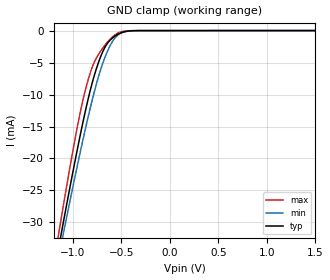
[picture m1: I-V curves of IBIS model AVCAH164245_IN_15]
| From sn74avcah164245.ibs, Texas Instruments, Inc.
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[Model]   AVCAH164245_IN_15
Model_type  Input
Vinl=0.49
Vinh=1.04
| variable   typ   min   max
C_comp   2.59pF   2.11pF   3.01pF
[Temperature Range]   40   100   -40
| Ambient temperature   25   85   -40
[Voltage range]   1.5   1.4   1.6
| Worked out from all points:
|   GND clamp passes 1 mA (typ) near -0.58 V on its own axis
[GND Clamp]
| AVCAH164245_IN_15
|   Voltage   I(typ)   I(min)   I(max)
-3.6V     -258.5mA   -242.3mA   -278mA
-1.165V   -35.44mA   -36.78mA   -33.39mA
-1.14V    -33.37mA   -34.87mA   -31.1mA
-1.115V   -31.31mA   -32.97mA   -28.83mA
-1.09V    -29.27mA   -31.08mA   -26.58mA
-950mV    -18.24mA   -20.81mA   -14.7mA
-840mV    -10.5mA    -13.3mA    -7.535mA
-780mV    -7.043mA   -9.603mA   -4.951mA
-705mV    -3.735mA   -5.691mA   -3.006mA
-585mV    -1.06mA    -1.53mA    -892.5uA
-380mV    -22.97uA   -30.19uA   -5.607uA
1.5V      138.7pA    855.7pA    21.09pA
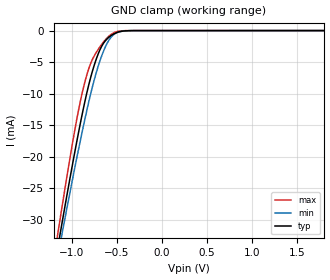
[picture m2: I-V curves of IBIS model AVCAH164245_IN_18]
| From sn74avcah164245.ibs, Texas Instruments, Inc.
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[Model]   AVCAH164245_IN_18
Model_type  Input
Vinl=0.5775
Vinh=1.2675
| variable   typ   min   max
C_comp   2.57pF   2.11pF   3.02pF
[Temperature Range]   40   100   -40
| Ambient temperature   25   85   -40
[Voltage range]   1.8   1.65   1.95
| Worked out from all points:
|   GND clamp passes 1 mA (typ) near -0.58 V on its own axis
[GND Clamp]
| AVCAH164245_IN_18
|   Voltage   I(typ)   I(min)   I(max)
-3.6V     -258.5mA   -242.3mA   -278mA
-1.15V    -34.2mA    -35.63mA   -32.02mA
-1.125V   -32.13mA   -33.73mA   -29.74mA
-1.1V     -30.08mA   -31.83mA   -27.48mA
-940mV    -17.49mA   -20.1mA    -13.94mA
-820mV    -9.271mA   -12.02mA   -6.55mA
-750mV    -5.585mA   -7.927mA   -4.068mA
-675mV    -2.758mA   -4.401mA   -2.383mA
-600mV    -1.25mA    -1.894mA   -1.094mA
-525mV    -489uA     -571uA     -316.1uA
-305mV    -2.806uA   -4.971uA   -342.3nA
1.8V      153pA      887.4pA    25.37pA
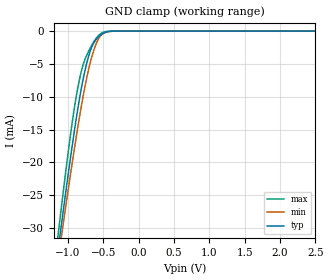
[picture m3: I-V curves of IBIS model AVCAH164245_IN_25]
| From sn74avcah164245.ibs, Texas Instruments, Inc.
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[Model]   AVCAH164245_IN_25
Model_type  Input
Vinl=0.7
Vinh=1.7
| variable   typ   min   max
C_comp   2.51pF   1.94pF   3.03pF
[Temperature Range]   40   100   -40
| Ambient temperature   25   85   -40
[Voltage range]   2.5   2.3   2.7
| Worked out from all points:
|   GND clamp passes 1 mA (typ) near -0.58 V on its own axis
[GND Clamp]
| AVCAH164245_IN_25
|   Voltage   I(typ)   I(min)   I(max)
-3.6V     -258.5mA   -242.3mA   -278mA
-1.135V   -32.95mA   -34.49mA   -30.65mA
-1.11V    -30.9mA    -32.59mA   -28.38mA
-1.085V   -28.86mA   -30.7mA    -26.14mA
-925mV    -16.38mA   -19.04mA   -12.82mA
-875mV    -12.81mA   -15.61mA   -9.498mA
-815mV    -8.975mA   -11.71mA   -6.321mA
-745mV    -5.359mA   -7.661mA   -3.939mA
-675mV    -2.758mA   -4.401mA   -2.383mA
-585mV    -1.06mA    -1.53mA    -892.5uA
-505mV    -356.6uA   -398.4uA   -204.9uA
2.5V      190pA      962.8pA    35.97pA
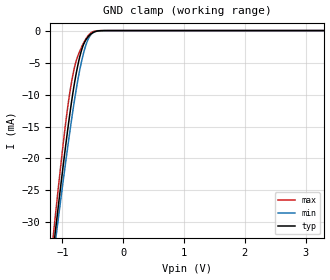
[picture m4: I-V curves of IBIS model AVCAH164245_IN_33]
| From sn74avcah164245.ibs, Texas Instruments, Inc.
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[Model]   AVCAH164245_IN_33
Model_type  Input
Vinl=0.8
Vinh=2
| variable   typ   min   max
C_comp   2.45pF   1.83pF   3.10pF
[Temperature Range]   40   100   -40
| Ambient temperature   25   85   -40
[Voltage range]   3.3   3   3.6
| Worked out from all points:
|   GND clamp passes 1 mA (typ) near -0.58 V on its own axis
[GND Clamp]
| AVCAH164245_IN_33
|   Voltage   I(typ)   I(min)   I(max)
-3.6V     -258.5mA   -242.3mA   -278mA
-1.16V    -35.03mA   -36.4mA    -32.93mA
-1.13V    -32.54mA   -34.11mA   -30.19mA
-1.105V   -30.49mA   -32.21mA   -27.93mA
-1.08V    -28.46mA   -30.33mA   -25.69mA
-935mV    -17.11mA   -19.74mA   -13.56mA
-815mV    -8.975mA   -11.71mA   -6.321mA
-750mV    -5.585mA   -7.927mA   -4.068mA
-675mV    -2.758mA   -4.401mA   -2.383mA
-590mV    -1.12mA    -1.646mA   -957.2uA
-500mV    -327.7uA   -363.5uA   -182.6uA
3.3V      240.1pA    1.053nA    49.57pA
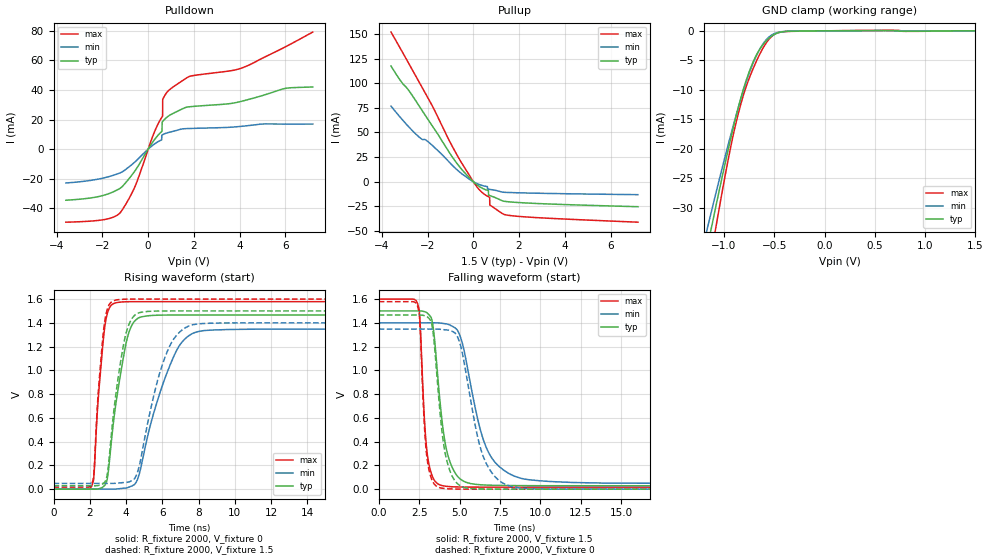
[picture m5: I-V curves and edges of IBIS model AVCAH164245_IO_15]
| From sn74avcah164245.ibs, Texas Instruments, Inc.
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[Model]   AVCAH164245_IO_15
Model_type  I/O
Vinl=0.49
Vinh=1.04
Enable   Active-Low
Vref =   0
Rref =   2000
Cref =   15p
Vmeas =   0.75
| variable   typ   min   max
C_comp   3.64pF   3.18pF   3.94pF
| C_pullup   2.35pF   0.32pF   4.30pF
| C_pulldown   3.11pF   0.98pF   4.70pF
| C_tri-state   3.64pF   3.18pF   3.94pF
[Temperature Range]   40   100   -40
| Ambient temperature   25   85   -40
[Voltage range]   1.5   1.4   1.6
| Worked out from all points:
|   slope of the pulldown table from 0 to 0.225 V, typ, clamps not added: 42 ohm
|   slope of the pullup table from 0 to 0.225 V, typ, clamps not added: 52.5 ohm
|   GND clamp passes 1 mA (typ) near -0.53 V on its own axis
|   rising waveform, R_fixture 2000, V_fixture 0: 20-80 % time 808ps typ, 1.58ns min, 449ps max; typ from 0 V to 1.47 V
|   falling waveform, R_fixture 2000, V_fixture 1.5: 20-80 % time 717ps typ, 1.42ns min, 370ps max; typ from 1.5 V to 0.029 V
|   rising waveform, R_fixture 2000, V_fixture 1.5: 20-80 % time 742ps typ, 1.31ns min, 428ps max; typ from 0.029 V to 1.5 V
|   falling waveform, R_fixture 2000, V_fixture 0: 20-80 % time 653ps typ, 1.22ns min, 348ps max; typ from 1.47 V to 0 V
[GND Clamp]
| AVCAH164245_IO_15
|   Voltage   I(typ)   I(min)   I(max)
-3.6V     -266.9mA   -231.6mA   -310.8mA
-1.17V    -37.13mA   -33.81mA   -42.25mA
-1.145V   -35.05mA   -32.04mA   -39.73mA
-1.12V    -32.98mA   -30.28mA   -37.22mA
-1.095V   -30.93mA   -28.54mA   -34.74mA
-1.07V    -28.91mA   -26.81mA   -32.29mA
-910mV    -16.61mA   -16.23mA   -17.83mA
-775mV    -8.202mA   -8.432mA   -9.247mA
-635mV    -2.878mA   -2.851mA   -3.659mA
-505mV    -672.1uA   -519.1uA   -682.9uA
-330mV    -58.96uA   -42.33uA   -86.88uA
1.5V      423.9pA    1.527uA    -44.14nA
[Pulldown]
| AVCAH164245_IO_15
|   Voltage   I(typ)   I(min)   I(max)
-3.6V     -34.57mA   -22.93mA   -49.45mA
-1.205V   -26.25mA   -15.91mA   -42.65mA
-545mV    -13.97mA   -8.197mA   -24.13mA
605mV     12.08mA    9.529mA    21.74mA
610mV     17.95mA    9.575mA    21.85mA
630mV     18.63mA    9.752mA    22.26mA
635mV     18.73mA    9.794mA    33.51mA
640mV     18.82mA    9.836mA    33.78mA
1.005V    23.49mA    11.71mA    41.12mA
1.815V    28.67mA    13.96mA    49.24mA
4.21V     32.88mA    15.63mA    55.57mA
7.2V      42.06mA    16.99mA    79.2mA
[Pullup]
| AVCAH164245_IO_15
|   Voltage   I(typ)   I(min)   I(max)
-3.6V     117.4mA    76.76mA    152mA
-2.53V    82.64mA    48.73mA    107.8mA
-1.915V   60.82mA    39.36mA    82.13mA
-685mV    17.59mA    11.5mA     25.93mA
160mV     -3.172mA   -1.894mA   -5.317mA
660mV     -9.044mA   -7.637mA   -15.18mA
665mV     -13.54mA   -7.655mA   -15.24mA
715mV     -14.07mA   -7.825mA   -15.71mA
720mV     -14.11mA   -7.841mA   -23.63mA
725mV     -14.15mA   -7.857mA   -23.74mA
1.66V     -20.65mA   -11.06mA   -34.53mA
7.2V      -25.41mA   -13.18mA   -41.13mA
[Ramp]
| AVCAH164245_IO_15
| variable   typ   min   max
dV/dt_r   0.88/8.11E-10   0.81/1.58E-09   0.95/4.52E-10
dV/dt_f   0.88/7.22E-10   0.81/1.42E-09   0.95/3.76E-10
R_load = 2000
[Rising Waveform]
| AVCAH164245_IO_15
R_fixture =   2000
C_fixture =   0
L_fixture =   0
V_fixture =   0
V_fixture_min = 0
V_fixture_max = 0
|   Time   V(typ)   V(min)   V(max)
0s        13.12nV    75.66nV    444pV
2.135ns   -83.33uV   516.5nV    35.8mV
2.825ns   32.55mV    -252.6uV   1.364V
3ns       122.9mV    -403.2uV   1.495V
3.415ns   693.4mV    636.2uV    1.567V
4.025ns   1.244V     10.28mV    1.577V
4.48ns    1.416V     41.32mV    1.578V
6.46ns    1.466V     1.056V     1.578V
7.925ns   1.466V     1.325V     1.578V
40ns      1.466V     1.347V     1.578V
[Falling Waveform]
| AVCAH164245_IO_15
R_fixture =   2000
C_fixture =   0
L_fixture =   0
V_fixture =   1.5
V_fixture_min = 1.4
V_fixture_max = 1.6
|   Time   V(typ)   V(min)   V(max)
0s        1.5V       1.4V       1.6V
2.405ns   1.5V       1.4V       1.561V
2.545ns   1.5V       1.4V       1.438V
3.01ns    1.482V     1.4V       290.8mV
3.37ns    1.361V     1.4V       92.23mV
3.865ns   638.5mV    1.397V     32.39mV
4.995ns   91.1mV     1.303V     18.3mV
6.645ns   34.54mV    352.4mV    16.91mV
8.755ns   29.77mV    92.98mV    16.76mV
40ns      28.72mV    48.24mV    16.74mV
[Rising Waveform]
| AVCAH164245_IO_15
R_fixture =   2000
C_fixture =   0
L_fixture =   0
V_fixture =   1.5
V_fixture_min = 1.4
V_fixture_max = 1.6
|   Time   V(typ)   V(min)   V(max)
0s        28.72mV    48.24mV    16.74mV
2.125ns   28.66mV    48.24mV    47.44mV
2.79ns    53.46mV    48.04mV    1.375V
2.99ns    150.3mV    47.86mV    1.525V
3.415ns   771.4mV    48.91mV    1.591V
3.95ns    1.281V     55.68mV    1.599V
4.425ns   1.456V     81.44mV    1.6V
6.17ns    1.5V       1.119V     1.6V
7.685ns   1.5V       1.384V     1.6V
40ns      1.5V       1.4V       1.6V
[Falling Waveform]
| AVCAH164245_IO_15
R_fixture =   2000
C_fixture =   0
L_fixture =   0
V_fixture =   0
V_fixture_min = 0
V_fixture_max = 0
|   Time   V(typ)   V(min)   V(max)
0s        1.466V     1.347V     1.578V
2.405ns   1.466V     1.347V     1.54V
2.54ns    1.466V     1.347V     1.416V
2.975ns   1.454V     1.347V     276.5mV
3.35ns    1.334V     1.347V     60.9mV
3.78ns    664.9mV    1.346V     12.39mV
4.795ns   56.95mV    1.301V     916.8uV
6.44ns    1.237mV    284.4mV    72.21uV
8.18ns    250.4uV    22.97mV    9.783uV
40ns      359.8nV    172.1nV    174.5nV
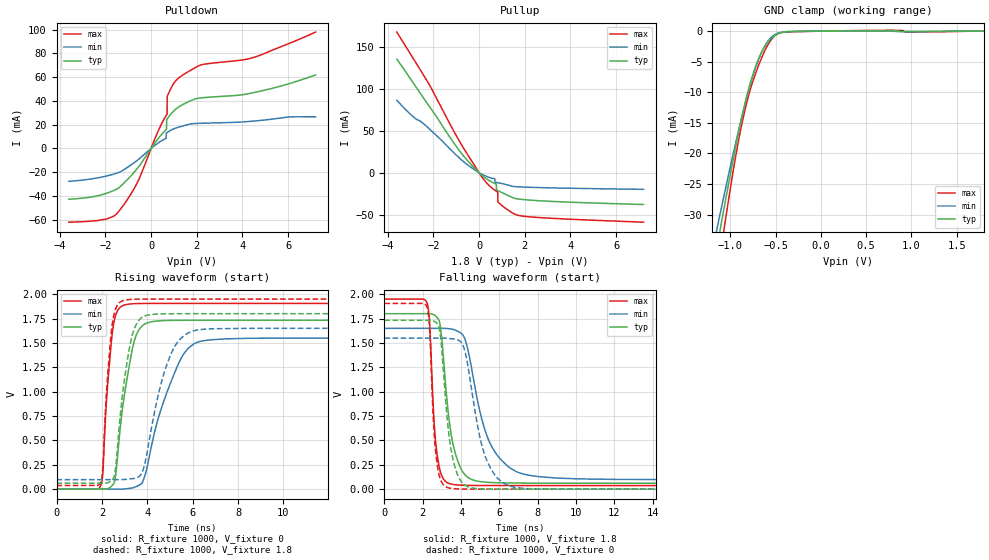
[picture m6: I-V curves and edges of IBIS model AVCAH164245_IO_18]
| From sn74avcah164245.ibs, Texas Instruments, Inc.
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[Model]   AVCAH164245_IO_18
Model_type  I/O
Vinl=0.5775
Vinh=1.2675
Enable   Active-Low
Vref =   0
Rref =   1000
Cref =   30p
Vmeas =   0.9
| variable   typ   min   max
C_comp   3.64pF   2.93pF   4.00pF
| C_pullup   2.34pF   0.00pF   4.95pF
| C_pulldown   2.85pF   0.02pF   5.86pF
| C_tri-state   3.64pF   2.93pF   4.00pF
[Temperature Range]   40   100   -40
| Ambient temperature   25   85   -40
[Voltage range]   1.8   1.65   1.95
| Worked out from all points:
|   slope of the pulldown table from 0 to 0.27 V, typ, clamps not added: 37 ohm
|   slope of the pullup table from 0 to 0.27 V, typ, clamps not added: 42.8 ohm
|   GND clamp passes 1 mA (typ) near -0.53 V on its own axis
|   rising waveform, R_fixture 1000, V_fixture 0: 20-80 % time 604ps typ, 1.22ns min, 337ps max; typ from 0 V to 1.73 V
|   falling waveform, R_fixture 1000, V_fixture 1.8: 20-80 % time 609ps typ, 1.23ns min, 315ps max; typ from 1.8 V to 0.061 V
|   rising waveform, R_fixture 1000, V_fixture 1.8: 20-80 % time 536ps typ, 943ps min, 315ps max; typ from 0.061 V to 1.8 V
|   falling waveform, R_fixture 1000, V_fixture 0: 20-80 % time 521ps typ, 936ps min, 286ps max; typ from 1.73 V to 0 V
[GND Clamp]
| AVCAH164245_IO_18
|   Voltage   I(typ)   I(min)   I(max)
-3.6V     -266.9mA   -231.6mA   -310.8mA
-1.16V    -36.3mA    -33.11mA   -41.26mA
-1.135V   -34.23mA   -31.34mA   -38.74mA
-1.11V    -32.17mA   -29.59mA   -36.25mA
-1.085V   -30.13mA   -27.85mA   -33.78mA
-1.06V    -28.11mA   -26.13mA   -31.34mA
-900mV    -15.91mA   -15.61mA   -17.08mA
-770mV    -7.963mA   -8.185mA   -9.024mA
-630mV    -2.766mA   -2.716mA   -3.517mA
-495mV    -591uA     -451.4uA   -597.6uA
-310mV    -60.48uA   -41uA      -96.57uA
1.8V      540.2pA    1.913uA    -414.8nA
[Pulldown]
| AVCAH164245_IO_18
|   Voltage   I(typ)   I(min)   I(max)
-3.6V     -42.79mA   -27.72mA   -62.09mA
-1.96V    -37.78mA   -23.22mA   -59.35mA
-1.32V    -31.55mA   -19.39mA   -50.62mA
-525mV    -14.89mA   -8.786mA   -25.56mA
675mV     16.06mA    13.11mA    28.29mA
680mV     24.06mA    13.18mA    28.45mA
700mV     24.84mA    13.45mA    28.97mA
705mV     24.97mA    13.51mA    43.55mA
710mV     25.1mA     13.58mA    44.03mA
1.24V     35.39mA    18.1mA     59.89mA
2.15V     42.51mA    21.17mA    70.2mA
7.2V      61.89mA    26.67mA    98mA
[Pullup]
| AVCAH164245_IO_18
|   Voltage   I(typ)   I(min)   I(max)
-3.6V     135.1mA    86.13mA    167.3mA
-2.17V    78.63mA    51.92mA    104.4mA
-735mV    21.83mA    14.38mA    31.76mA
205mV     -4.937mA   -2.977mA   -8.062mA
755mV     -13.49mA   -11.54mA   -22.08mA
765mV     -20.38mA   -11.61mA   -22.27mA
820mV     -21.24mA   -11.95mA   -23.2mA
825mV     -21.31mA   -11.98mA   -33.95mA
830mV     -21.39mA   -12.01mA   -34.93mA
1.07V     -24.65mA   -13.46mA   -40.62mA
2.025V    -32.3mA    -17.28mA   -52.12mA
7.2V      -37.96mA   -19.91mA   -59mA
[Ramp]
| AVCAH164245_IO_18
| variable   typ   min   max
dV/dt_r   1.04/6.07E-10   0.93/1.22E-09   1.14/3.39E-10
dV/dt_f   1.04/6.11E-10   0.93/1.23E-09   1.15/3.20E-10
R_load = 1000
[Rising Waveform]
| AVCAH164245_IO_18
R_fixture =   1000
C_fixture =   0
L_fixture =   0
V_fixture =   0
V_fixture_min = 0
V_fixture_max = 0
|   Time   V(typ)   V(min)   V(max)
0s        13.14nV    68.1nV     511pV
1.99ns    -233.8uV   1.585uV    62.74mV
2.23ns    2.995mV    13.5uV     998mV
2.485ns   46.67mV    -172.4uV   1.649V
3.085ns   1.101V     3.615mV    1.895V
3.44ns    1.529V     18.78mV    1.903V
3.815ns   1.682V     85.86mV    1.905V
5.26ns    1.732V     1.225V     1.905V
6.4ns     1.733V     1.52V      1.905V
40ns      1.732V     1.55V      1.905V
[Falling Waveform]
| AVCAH164245_IO_18
R_fixture =   1000
C_fixture =   0
L_fixture =   0
V_fixture =   1.8
V_fixture_min = 1.65
V_fixture_max = 1.95
|   Time   V(typ)   V(min)   V(max)
0s        1.8V       1.65V      1.95V
2.245ns   1.8V       1.65V      1.899V
2.35ns    1.8V       1.65V      1.732V
2.735ns   1.762V     1.65V      376.5mV
2.955ns   1.611V     1.65V      155.8mV
3.465ns   582.9mV    1.643V     52.93mV
4.205ns   147.7mV    1.537V     39.6mV
5.57ns    68.47mV    447mV      37.32mV
7.34ns    62.1mV     150.7mV    37.11mV
40ns      60.82mV    97.4mV     37.09mV
[Rising Waveform]
| AVCAH164245_IO_18
R_fixture =   1000
C_fixture =   0
L_fixture =   0
V_fixture =   1.8
V_fixture_min = 1.65
V_fixture_max = 1.95
|   Time   V(typ)   V(min)   V(max)
0s        60.82mV    97.39mV    37.09mV
1.97ns    60.68mV    97.4mV     86.97mV
2.225ns   63.48mV    97.41mV    1.077V
2.45ns    93.08mV    97.31mV    1.681V
2.605ns   220.4mV    96.92mV    1.848V
3.03ns    1.182V     99.64mV    1.94V
3.72ns    1.754V     149.7mV    1.949V
4.955ns   1.799V     1.336V     1.95V
6.17ns    1.8V       1.632V     1.95V
40ns      1.8V       1.65V      1.95V
[Falling Waveform]
| AVCAH164245_IO_18
R_fixture =   1000
C_fixture =   0
L_fixture =   0
V_fixture =   0
V_fixture_min = 0
V_fixture_max = 0
|   Time   V(typ)   V(min)   V(max)
0s        1.732V     1.55V      1.905V
2.24ns    1.733V     1.55V      1.858V
2.345ns   1.732V     1.55V      1.68V
2.7ns     1.708V     1.55V      330.6mV
2.935ns   1.549V     1.55V      93.68mV
3.365ns   558.1mV    1.546V     12.73mV
4.16ns    47.29mV    1.44V      1.098mV
5.255ns   2.01mV     339mV      116.5uV
6.765ns   275.3uV    20.65mV    13.05uV
40ns      303.8nV    144.5nV    230nV
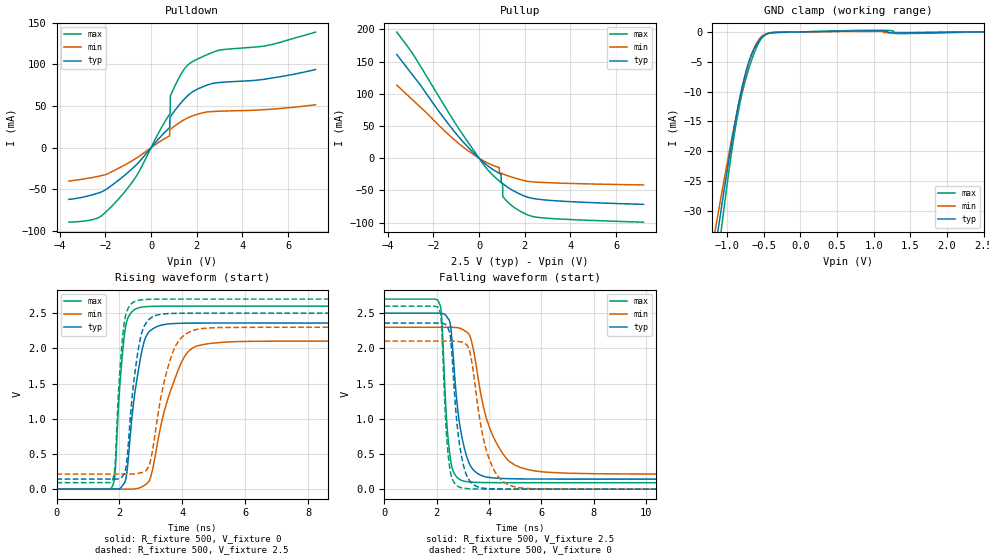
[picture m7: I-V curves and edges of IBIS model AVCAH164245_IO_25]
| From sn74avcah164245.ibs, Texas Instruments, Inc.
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[Model]   AVCAH164245_IO_25
Model_type  I/O
Vinl=0.7
Vinh=1.7
Enable   Active-Low
Vref =   0
Rref =   500
Cref =   30p
Vmeas =   1.25
| variable   typ   min   max
C_comp   3.59pF   3.04pF   3.99pF
| C_pullup   2.75pF   0.07pF   6.57pF
| C_pulldown   2.74pF   0.59pF   8.63pF
| C_tri-state   3.59pF   3.04pF   3.99pF
[Temperature Range]   40   100   -40
| Ambient temperature   25   85   -40
[Voltage range]   2.5   2.3   2.7
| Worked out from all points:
|   slope of the pulldown table from 0 to 0.375 V, typ, clamps not added: 31.5 ohm
|   slope of the pullup table from 0 to 0.375 V, typ, clamps not added: 32 ohm
|   GND clamp passes 1 mA (typ) near -0.53 V on its own axis
|   rising waveform, R_fixture 500, V_fixture 0: 20-80 % time 390ps typ, 742ps min, 232ps max; typ from 0 V to 2.36 V
|   falling waveform, R_fixture 500, V_fixture 2.5: 20-80 % time 434ps typ, 867ps min, 237ps max; typ from 2.5 V to 0.143 V
|   rising waveform, R_fixture 500, V_fixture 2.5: 20-80 % time 338ps typ, 564ps min, 212ps max; typ from 0.143 V to 2.5 V
|   falling waveform, R_fixture 500, V_fixture 0: 20-80 % time 360ps typ, 623ps min, 213ps max; typ from 2.36 V to 0 V
[GND Clamp]
| AVCAH164245_IO_25
|   Voltage   I(typ)   I(min)   I(max)
-3.6V     -267mA     -231.6mA   -310.8mA
-1.155V   -35.91mA   -32.76mA   -40.78mA
-1.1V     -31.37mA   -28.9mA    -35.29mA
-1.075V   -29.34mA   -27.17mA   -32.83mA
-905mV    -16.28mA   -15.94mA   -17.5mA
-795mV    -9.281mA   -9.494mA   -10.32mA
-715mV    -5.522mA   -5.67mA    -6.66mA
-635mV    -2.912mA   -2.872mA   -3.714mA
-555mV    -1.334mA   -1.108mA   -1.548mA
-485mV    -532.6uA   -403.2uA   -545.5uA
715mV     129.7uA    77.97uA    229.8uA
2.5V      713.1pA    2.241uA    -2.92uA
[Pulldown]
| AVCAH164245_IO_25
|   Voltage   I(typ)   I(min)   I(max)
-3.6V     -62.13mA   -40.06mA   -89.46mA
-2.25V    -53.9mA    -34.03mA   -83.25mA
-955mV    -28.39mA   -17.71mA   -46.13mA
810mV     23.97mA    14.1mA     40.04mA
820mV     24.18mA    21.47mA    40.42mA
825mV     35.65mA    21.58mA    40.6mA
835mV     36.98mA    21.8mA     40.97mA
840mV     37.18mA    21.91mA    60.5mA
850mV     37.56mA    22.12mA    62.56mA
1.67V     63.99mA    36.6mA     100.6mA
2.72V     77.25mA    43.4mA     114.6mA
7.2V      93.77mA    51.51mA    138.7mA
[Pullup]
| AVCAH164245_IO_25
|   Voltage   I(typ)   I(min)   I(max)
-3.6V     161.2mA    113.5mA    196mA
-885mV    33.04mA    22.76mA    45.8mA
250mV     -8.097mA   -5.221mA   -12.31mA
885mV     -23.45mA   -14.56mA   -35.4mA
965mV     -24.96mA   -23.2mA    -37.96mA
975mV     -37.05mA   -23.35mA   -38.27mA
1.03V     -39.29mA   -24.18mA   -39.86mA
1.04V     -39.57mA   -24.33mA   -57.7mA
1.05V     -39.85mA   -24.48mA   -59.88mA
1.465V    -49.86mA   -29.73mA   -74.63mA
2.6V      -63.81mA   -37.35mA   -92.06mA
7.2V      -71.76mA   -41.58mA   -99.46mA
[Ramp]
| AVCAH164245_IO_25
| variable   typ   min   max
dV/dt_r   1.42/3.91E-10   1.26/7.44E-10   1.56/2.32E-10
dV/dt_f   1.41/4.35E-10   1.25/8.68E-10   1.57/2.38E-10
R_load = 500
[Rising Waveform]
| AVCAH164245_IO_25
R_fixture =   500
C_fixture =   0
L_fixture =   0
V_fixture =   0
V_fixture_min = 0
V_fixture_max = 0
|   Time   V(typ)   V(min)   V(max)
0s        14.87nV    61.7nV     722.3pV
1.775ns   -130.5uV   -213.9nV   42.89mV
1.855ns   -270.6uV   2.921uV    200.3mV
2.01ns    7.942mV    21.67uV    1.466V
2.19ns    124.5mV    -423.9uV   2.296V
2.725ns   1.994V     35.57mV    2.586V
2.98ns    2.252V     157.5mV    2.596V
3.965ns   2.356V     1.798V     2.599V
4.895ns   2.359V     2.07V      2.599V
40ns      2.359V     2.103V     2.599V
[Falling Waveform]
| AVCAH164245_IO_25
R_fixture =   500
C_fixture =   0
L_fixture =   0
V_fixture =   2.5
V_fixture_min = 2.3
V_fixture_max = 2.7
|   Time   V(typ)   V(min)   V(max)
0s        2.5V       2.3V       2.7V
2.065ns   2.5V       2.3V       2.666V
2.185ns   2.497V     2.3V       2.458V
2.365ns   2.46V      2.3V       1.053V
2.53ns    2.312V     2.3V       417.5mV
2.81ns    1.11V      2.293V     156mV
3.1ns     522.4mV    2.242V     109.6mV
4.225ns   157.6mV    697.1mV    92.46mV
5.76ns    144.2mV    258.9mV    91.78mV
40ns      142.7mV    213.8mV    91.75mV
[Rising Waveform]
| AVCAH164245_IO_25
R_fixture =   500
C_fixture =   0
L_fixture =   0
V_fixture =   2.5
V_fixture_min = 2.3
V_fixture_max = 2.7
|   Time   V(typ)   V(min)   V(max)
0s        142.7mV    213.8mV    91.75mV
1.775ns   142.6mV    213.8mV    127.2mV
1.855ns   142.5mV    213.8mV    310.5mV
1.99ns    148.3mV    213.8mV    1.538V
2.155ns   221.2mV    213.5mV    2.372V
2.665ns   2.144V     231mV      2.687V
2.965ns   2.422V     371.6mV    2.697V
3.725ns   2.497V     1.979V     2.7V
4.62ns    2.5V       2.281V     2.7V
40ns      2.5V       2.3V       2.7V
[Falling Waveform]
| AVCAH164245_IO_25
R_fixture =   500
C_fixture =   0
L_fixture =   0
V_fixture =   0
V_fixture_min = 0
V_fixture_max = 0
|   Time   V(typ)   V(min)   V(max)
0s        2.359V     2.103V     2.599V
2.09ns    2.359V     2.103V     2.548V
2.185ns   2.356V     2.103V     2.321V
2.345ns   2.336V     2.103V     945.9mV
2.485ns   2.235V     2.103V     332.9mV
3.005ns   366.9mV    2.082V     15.3mV
3.28ns    110.4mV    1.928V     5.223mV
4.02ns    6.486mV    416.8mV    488.6uV
5.14ns    491.6uV    21.28mV    38.14uV
40ns      439.8nV    192.5nV    237.9nV
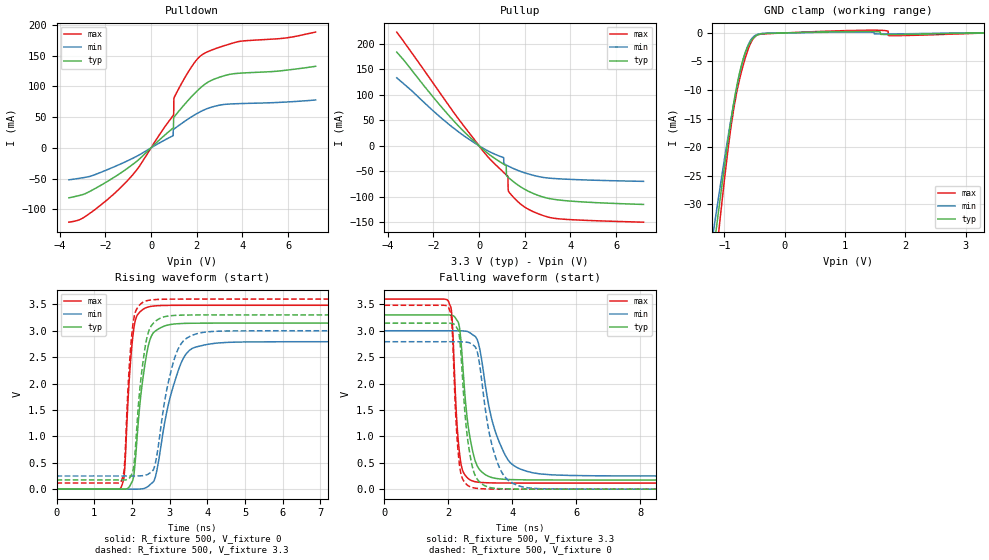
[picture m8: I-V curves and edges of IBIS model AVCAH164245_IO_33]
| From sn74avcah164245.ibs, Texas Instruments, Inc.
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[Model]   AVCAH164245_IO_33
Model_type  I/O
Vinl=0.8
Vinh=2
Enable   Active-Low
Vref =   0
Rref =   500
Cref =   30p
Vmeas =   1.65
| variable   typ   min   max
C_comp   3.52pF   2.98pF   3.90pF
| C_pullup   3.01pF   0.06pF   5.75pF
| C_pulldown   2.74pF   0.03pF   6.32pF
| C_tri-state   3.52pF   2.98pF   3.90pF
[Temperature Range]   40   100   -40
| Ambient temperature   25   85   -40
[Voltage range]   3.3   3   3.6
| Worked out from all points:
|   slope of the pulldown table from 0 to 0.495 V, typ, clamps not added: 28.7 ohm
|   slope of the pullup table from 0 to 0.495 V, typ, clamps not added: 26.6 ohm
|   GND clamp passes 1 mA (typ) near -0.53 V on its own axis
|   rising waveform, R_fixture 500, V_fixture 0: 20-80 % time 280ps typ, 511ps min, 175ps max; typ from 0 V to 3.14 V
|   falling waveform, R_fixture 500, V_fixture 3.3: 20-80 % time 321ps typ, 618ps min, 182ps max; typ from 3.3 V to 0.173 V
|   rising waveform, R_fixture 500, V_fixture 3.3: 20-80 % time 253ps typ, 422ps min, 165ps max; typ from 0.173 V to 3.3 V
|   falling waveform, R_fixture 500, V_fixture 0: 20-80 % time 284ps typ, 496ps min, 169ps max; typ from 3.14 V to 0 V
[GND Clamp]
| AVCAH164245_IO_33
|   Voltage   I(typ)   I(min)   I(max)
-3.6V     -267mA     -231.6mA   -310.9mA
-1.17V    -37.18mA   -33.84mA   -42.33mA
-1.115V   -32.61mA   -29.96mA   -36.81mA
-1.09V    -30.57mA   -28.22mA   -34.33mA
-905mV    -16.3mA    -15.95mA   -17.52mA
-795mV    -9.302mA   -9.506mA   -10.35mA
-635mV    -2.934mA   -2.886mA   -3.746mA
-470mV    -449uA     -337uA     -469.3uA
1.38V     248.6uA    138.4uA    461uA
1.7V      -292.6uA   -185.3uA   345.1uA
1.74V     -293.3uA   -183uA     -473.3uA
3.3V      842.6pA    4.65uA     -25.47uA
[Pulldown]
| AVCAH164245_IO_33
|   Voltage   I(typ)   I(min)   I(max)
-3.6V     -81.39mA   -52.07mA   -121mA
-2.39V    -64.98mA   -42.68mA   -98.54mA
-660mV    -22.85mA   -14.35mA   -37.45mA
965mV     32.09mA    19.61mA    52.39mA
980mV     32.51mA    29.96mA    53.08mA
985mV     47.58mA    30.11mA    53.31mA
990mV     48.91mA    30.25mA    56.17mA
995mV     49.48mA    30.39mA    78.14mA
1.015V    50.53mA    30.94mA    82.24mA
2.185V    98.28mA    59.27mA    150.1mA
3.48V     119.7mA    71.28mA    169.3mA
7.2V      132.6mA    77.76mA    188.2mA
[Pullup]
| AVCAH164245_IO_33
|   Voltage   I(typ)   I(min)   I(max)
-3.6V     183.5mA    133.2mA    222.8mA
-875mV    37.62mA    26.48mA    51.14mA
1.08V     -36.11mA   -23.28mA   -52.32mA
1.09V     -36.39mA   -35.07mA   -52.74mA
1.19V     -39.13mA   -37.69mA   -56.93mA
1.205V    -58.01mA   -38.04mA   -57.54mA
1.265V    -61.41mA   -39.43mA   -59.91mA
1.275V    -61.8mA    -39.66mA   -85.04mA
1.3V      -62.78mA   -40.22mA   -89.94mA
1.87V     -81.88mA   -51.11mA   -116mA
3.29V     -105.1mA   -64.2mA    -142.1mA
7.2V      -115mA     -69.79mA   -149.8mA
[Ramp]
| AVCAH164245_IO_33
| variable   typ   min   max
dV/dt_r   1.89/2.80E-10   1.68/5.12E-10   2.09/1.76E-10
dV/dt_f   1.88/3.22E-10   1.65/6.18E-10   2.09/1.82E-10
R_load = 500
[Rising Waveform]
| AVCAH164245_IO_33
R_fixture =   500
C_fixture =   0
L_fixture =   0
V_fixture =   0
V_fixture_min = 0
V_fixture_max = 0
|   Time   V(typ)   V(min)   V(max)
0s        19.06nV    64.42nV    1.161nV
1.71ns    -77.55uV   1.431uV    29.43mV
1.8ns     260.4uV    4.049uV    296.7mV
1.935ns   49.38mV    -32.99uV   2.131V
2.065ns   351.2mV    -640.1uV   3.106V
2.285ns   2.062V     6.98mV     3.4V
2.55ns    2.942V     125.4mV    3.466V
3.325ns   3.137V     2.42V      3.482V
4.24ns    3.144V     2.765V     3.482V
40ns      3.144V     2.792V     3.482V
[Falling Waveform]
| AVCAH164245_IO_33
R_fixture =   500
C_fixture =   0
L_fixture =   0
V_fixture =   3.3
V_fixture_min = 3
V_fixture_max = 3.6
|   Time   V(typ)   V(min)   V(max)
0s        3.3V       3V         3.6V
2ns       3.3V       3V         3.559V
2.11ns    3.293V     3V         3.285V
2.26ns    3.205V     3V         1.329V
2.385ns   2.864V     2.999V     516.1mV
2.605ns   1.261V     2.984V     209.2mV
2.9ns     444mV      2.834V     135.3mV
3.71ns    189mV      727.9mV    116.4mV
4.87ns    174.5mV    288.7mV    115.3mV
40ns      173.1mV    248.6mV    115.3mV
[Rising Waveform]
| AVCAH164245_IO_33
R_fixture =   500
C_fixture =   0
L_fixture =   0
V_fixture =   3.3
V_fixture_min = 3
V_fixture_max = 3.6
|   Time   V(typ)   V(min)   V(max)
0s        173.1mV    248.6mV    115.3mV
1.715ns   173mV      248.6mV    148.4mV
1.795ns   173.3mV    248.6mV    381.5mV
1.925ns   203.4mV    248.6mV    2.259V
2.045ns   416.3mV    248mV      3.206V
2.27ns    2.277V     254.2mV    3.529V
2.505ns   3.085V     323.9mV    3.583V
3.19ns    3.292V     2.595V     3.599V
4.005ns   3.3V       2.98V      3.6V
40ns      3.3V       3V         3.6V
[Falling Waveform]
| AVCAH164245_IO_33
R_fixture =   500
C_fixture =   0
L_fixture =   0
V_fixture =   0
V_fixture_min = 0
V_fixture_max = 0
|   Time   V(typ)   V(min)   V(max)
0s        3.144V     2.792V     3.482V
2.005ns   3.144V     2.792V     3.442V
2.105ns   3.138V     2.792V     3.178V
2.245ns   3.074V     2.792V     1.224V
2.365ns   2.776V     2.792V     385.3mV
2.58ns    1.058V     2.783V     84.39mV
2.85ns    244.1mV    2.685V     18.62mV
3.54ns    12.33mV    494.9mV    1.254mV
4.51ns    742.1uV    23.83mV    74.28uV
40ns      512.4nV    552.9nV    204.2nV
